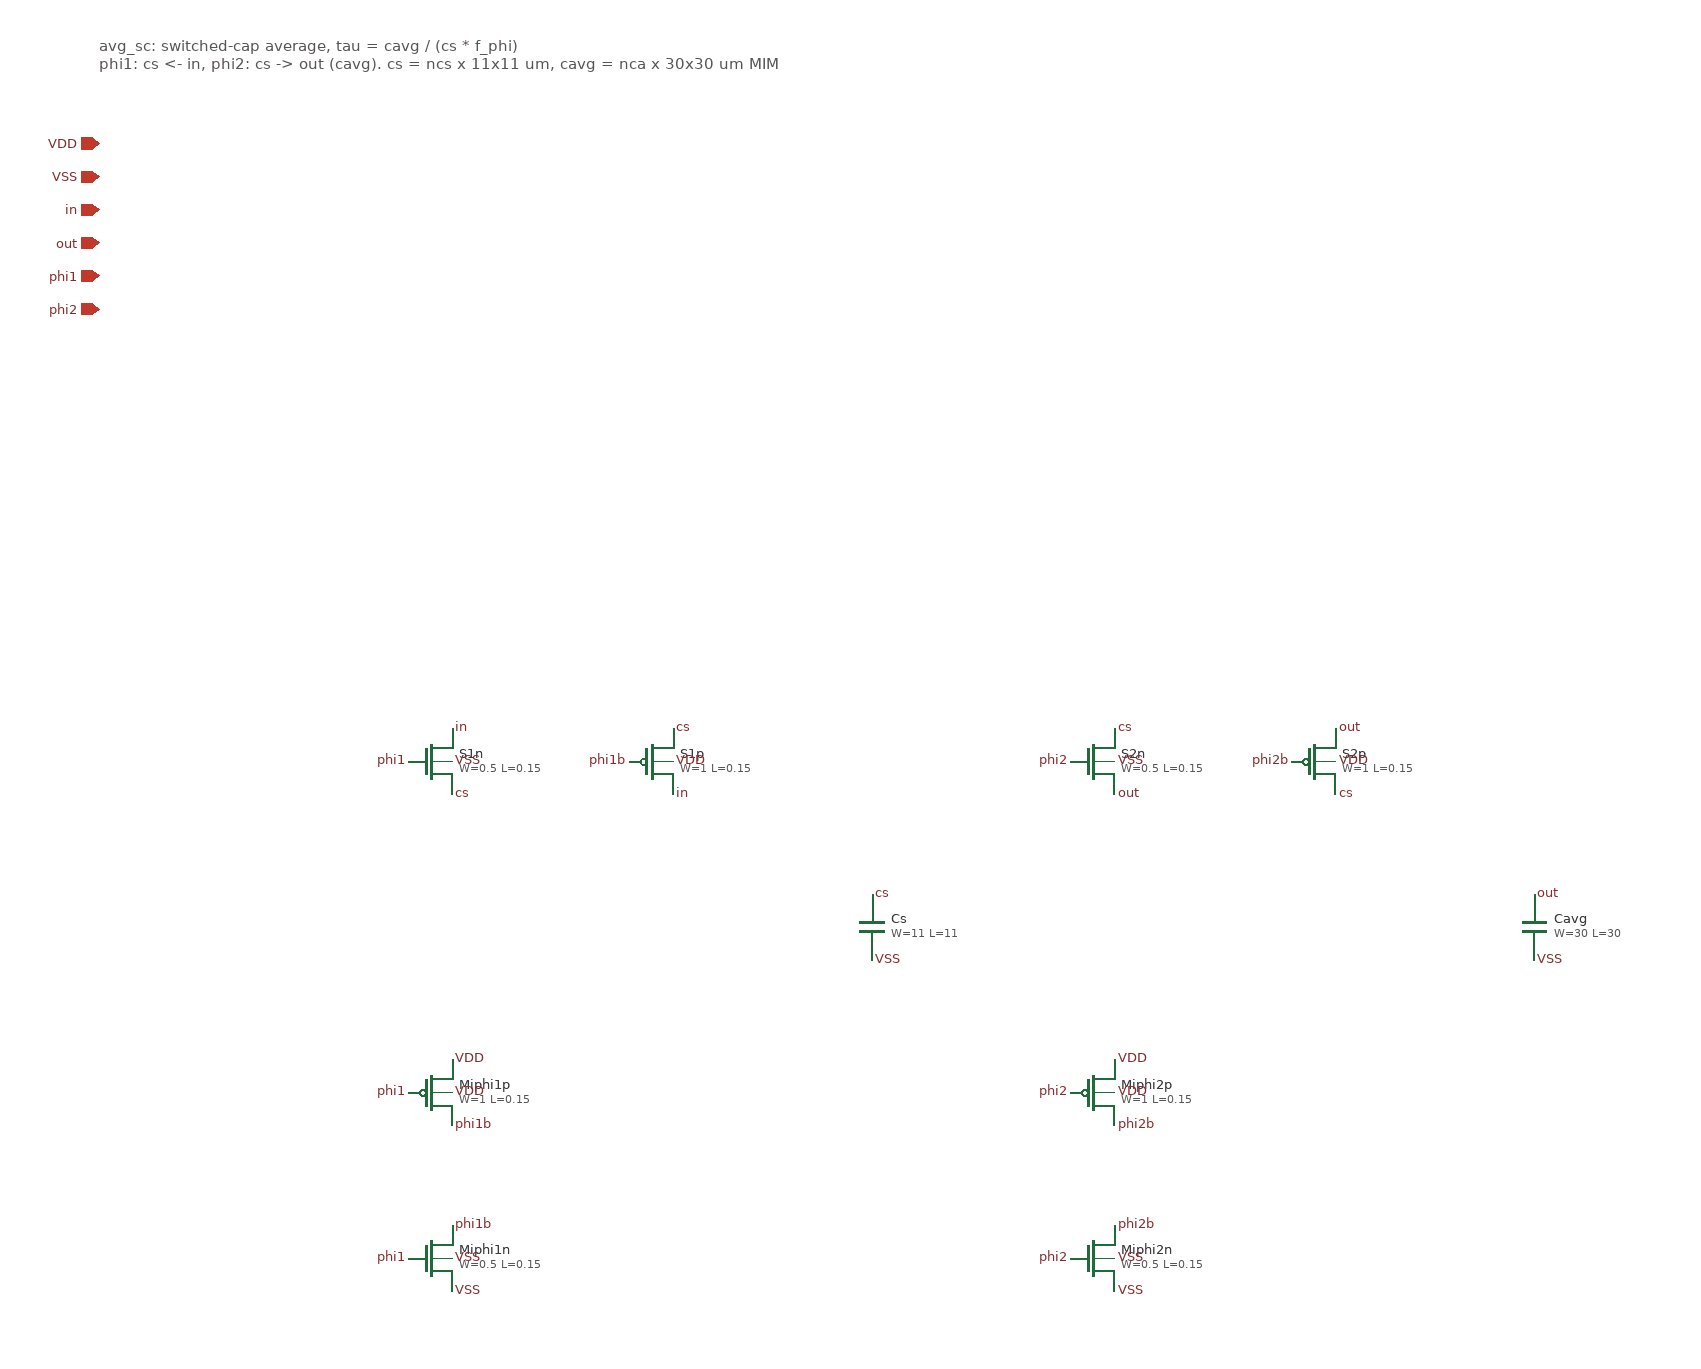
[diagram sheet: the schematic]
v {xschem version=3.4.5 file_version=1.2
}
G {}
K {}
V {}
S {}
E {}
T {avg_sc: switched-cap average, tau = cavg / (cs * f_phi)
phi1: cs <- in, phi2: cs -> out (cavg). cs = ncs x 11x11 um, cavg = nca x 30x30 um MIM} -600 -660 0 0 0.4 0.4 {}
C {devices/iopin.sym} -600 -560 0 0 {name=p1
lab=VDD}
C {devices/iopin.sym} -600 -530 0 0 {name=p2
lab=VSS}
C {devices/iopin.sym} -600 -500 0 0 {name=p3
lab=in}
C {devices/iopin.sym} -600 -470 0 0 {name=p4
lab=out}
C {devices/iopin.sym} -600 -440 0 0 {name=p5
lab=phi1}
C {devices/iopin.sym} -600 -410 0 0 {name=p6
lab=phi2}
C {sky130_fd_pr/pfet_01v8.sym} -300 300 0 0 {name=Miphi1p
nf=1
mult=1
ad="'int((nf+1)/2) * W/nf * 0.29'"
pd="'2*int((nf+1)/2) * (W/nf + 0.29)'"
as="'int((nf+2)/2) * W/nf * 0.29'"
ps="'2*int((nf+2)/2) * (W/nf + 0.29)'"
nrd="'0.29 / W'"
nrs="'0.29 / W'"
sa=0
sb=0
sd=0
L=0.15
W=1
model=pfet_01v8
spiceprefix=X}
C {devices/lab_pin.sym} -280 330 0 1 {name=p7
sig_type=std_logic
lab=phi1b}
C {devices/lab_pin.sym} -320 300 0 0 {name=p8
sig_type=std_logic
lab=phi1}
C {devices/lab_pin.sym} -280 270 0 1 {name=p9
sig_type=std_logic
lab=VDD}
C {devices/lab_pin.sym} -280 300 0 1 {name=p10
sig_type=std_logic
lab=VDD}
C {sky130_fd_pr/nfet_01v8.sym} -300 450 0 0 {name=Miphi1n
nf=1
mult=1
ad="'int((nf+1)/2) * W/nf * 0.29'"
pd="'2*int((nf+1)/2) * (W/nf + 0.29)'"
as="'int((nf+2)/2) * W/nf * 0.29'"
ps="'2*int((nf+2)/2) * (W/nf + 0.29)'"
nrd="'0.29 / W'"
nrs="'0.29 / W'"
sa=0
sb=0
sd=0
L=0.15
W=0.5
model=nfet_01v8
spiceprefix=X}
C {devices/lab_pin.sym} -280 420 0 1 {name=p11
sig_type=std_logic
lab=phi1b}
C {devices/lab_pin.sym} -320 450 0 0 {name=p12
sig_type=std_logic
lab=phi1}
C {devices/lab_pin.sym} -280 480 0 1 {name=p13
sig_type=std_logic
lab=VSS}
C {devices/lab_pin.sym} -280 450 0 1 {name=p14
sig_type=std_logic
lab=VSS}
C {sky130_fd_pr/pfet_01v8.sym} 300 300 0 0 {name=Miphi2p
nf=1
mult=1
ad="'int((nf+1)/2) * W/nf * 0.29'"
pd="'2*int((nf+1)/2) * (W/nf + 0.29)'"
as="'int((nf+2)/2) * W/nf * 0.29'"
ps="'2*int((nf+2)/2) * (W/nf + 0.29)'"
nrd="'0.29 / W'"
nrs="'0.29 / W'"
sa=0
sb=0
sd=0
L=0.15
W=1
model=pfet_01v8
spiceprefix=X}
C {devices/lab_pin.sym} 320 330 0 1 {name=p15
sig_type=std_logic
lab=phi2b}
C {devices/lab_pin.sym} 280 300 0 0 {name=p16
sig_type=std_logic
lab=phi2}
C {devices/lab_pin.sym} 320 270 0 1 {name=p17
sig_type=std_logic
lab=VDD}
C {devices/lab_pin.sym} 320 300 0 1 {name=p18
sig_type=std_logic
lab=VDD}
C {sky130_fd_pr/nfet_01v8.sym} 300 450 0 0 {name=Miphi2n
nf=1
mult=1
ad="'int((nf+1)/2) * W/nf * 0.29'"
pd="'2*int((nf+1)/2) * (W/nf + 0.29)'"
as="'int((nf+2)/2) * W/nf * 0.29'"
ps="'2*int((nf+2)/2) * (W/nf + 0.29)'"
nrd="'0.29 / W'"
nrs="'0.29 / W'"
sa=0
sb=0
sd=0
L=0.15
W=0.5
model=nfet_01v8
spiceprefix=X}
C {devices/lab_pin.sym} 320 420 0 1 {name=p19
sig_type=std_logic
lab=phi2b}
C {devices/lab_pin.sym} 280 450 0 0 {name=p20
sig_type=std_logic
lab=phi2}
C {devices/lab_pin.sym} 320 480 0 1 {name=p21
sig_type=std_logic
lab=VSS}
C {devices/lab_pin.sym} 320 450 0 1 {name=p22
sig_type=std_logic
lab=VSS}
C {sky130_fd_pr/nfet_01v8.sym} -300 0 0 0 {name=S1n
nf=1
mult=1
ad="'int((nf+1)/2) * W/nf * 0.29'"
pd="'2*int((nf+1)/2) * (W/nf + 0.29)'"
as="'int((nf+2)/2) * W/nf * 0.29'"
ps="'2*int((nf+2)/2) * (W/nf + 0.29)'"
nrd="'0.29 / W'"
nrs="'0.29 / W'"
sa=0
sb=0
sd=0
L=0.15
W=0.5
model=nfet_01v8
spiceprefix=X}
C {devices/lab_pin.sym} -280 -30 0 1 {name=p23
sig_type=std_logic
lab=in}
C {devices/lab_pin.sym} -320 0 0 0 {name=p24
sig_type=std_logic
lab=phi1}
C {devices/lab_pin.sym} -280 30 0 1 {name=p25
sig_type=std_logic
lab=cs}
C {devices/lab_pin.sym} -280 0 0 1 {name=p26
sig_type=std_logic
lab=VSS}
C {sky130_fd_pr/pfet_01v8.sym} -100 0 0 0 {name=S1p
nf=1
mult=1
ad="'int((nf+1)/2) * W/nf * 0.29'"
pd="'2*int((nf+1)/2) * (W/nf + 0.29)'"
as="'int((nf+2)/2) * W/nf * 0.29'"
ps="'2*int((nf+2)/2) * (W/nf + 0.29)'"
nrd="'0.29 / W'"
nrs="'0.29 / W'"
sa=0
sb=0
sd=0
L=0.15
W=1
model=pfet_01v8
spiceprefix=X}
C {devices/lab_pin.sym} -80 30 0 1 {name=p27
sig_type=std_logic
lab=in}
C {devices/lab_pin.sym} -120 0 0 0 {name=p28
sig_type=std_logic
lab=phi1b}
C {devices/lab_pin.sym} -80 -30 0 1 {name=p29
sig_type=std_logic
lab=cs}
C {devices/lab_pin.sym} -80 0 0 1 {name=p30
sig_type=std_logic
lab=VDD}
C {sky130_fd_pr/nfet_01v8.sym} 300 0 0 0 {name=S2n
nf=1
mult=1
ad="'int((nf+1)/2) * W/nf * 0.29'"
pd="'2*int((nf+1)/2) * (W/nf + 0.29)'"
as="'int((nf+2)/2) * W/nf * 0.29'"
ps="'2*int((nf+2)/2) * (W/nf + 0.29)'"
nrd="'0.29 / W'"
nrs="'0.29 / W'"
sa=0
sb=0
sd=0
L=0.15
W=0.5
model=nfet_01v8
spiceprefix=X}
C {devices/lab_pin.sym} 320 -30 0 1 {name=p31
sig_type=std_logic
lab=cs}
C {devices/lab_pin.sym} 280 0 0 0 {name=p32
sig_type=std_logic
lab=phi2}
C {devices/lab_pin.sym} 320 30 0 1 {name=p33
sig_type=std_logic
lab=out}
C {devices/lab_pin.sym} 320 0 0 1 {name=p34
sig_type=std_logic
lab=VSS}
C {sky130_fd_pr/pfet_01v8.sym} 500 0 0 0 {name=S2p
nf=1
mult=1
ad="'int((nf+1)/2) * W/nf * 0.29'"
pd="'2*int((nf+1)/2) * (W/nf + 0.29)'"
as="'int((nf+2)/2) * W/nf * 0.29'"
ps="'2*int((nf+2)/2) * (W/nf + 0.29)'"
nrd="'0.29 / W'"
nrs="'0.29 / W'"
sa=0
sb=0
sd=0
L=0.15
W=1
model=pfet_01v8
spiceprefix=X}
C {devices/lab_pin.sym} 520 30 0 1 {name=p35
sig_type=std_logic
lab=cs}
C {devices/lab_pin.sym} 480 0 0 0 {name=p36
sig_type=std_logic
lab=phi2b}
C {devices/lab_pin.sym} 520 -30 0 1 {name=p37
sig_type=std_logic
lab=out}
C {devices/lab_pin.sym} 520 0 0 1 {name=p38
sig_type=std_logic
lab=VDD}
C {sky130_fd_pr/cap_mim_m3_1.sym} 100 150 0 0 {name=Cs
model=cap_mim_m3_1
W=11
L=11
MF='ncs'
spiceprefix=X}
C {devices/lab_pin.sym} 100 120 0 1 {name=p39
sig_type=std_logic
lab=cs}
C {devices/lab_pin.sym} 100 180 0 1 {name=p40
sig_type=std_logic
lab=VSS}
C {sky130_fd_pr/cap_mim_m3_1.sym} 700 150 0 0 {name=Cavg
model=cap_mim_m3_1
W=30
L=30
MF='nca'
spiceprefix=X}
C {devices/lab_pin.sym} 700 120 0 1 {name=p41
sig_type=std_logic
lab=out}
C {devices/lab_pin.sym} 700 180 0 1 {name=p42
sig_type=std_logic
lab=VSS}
